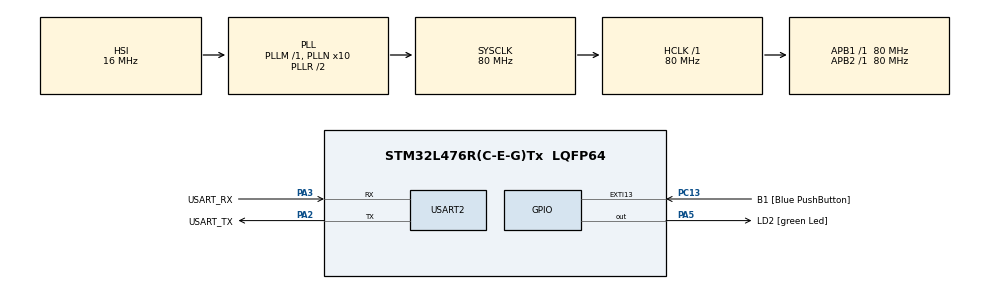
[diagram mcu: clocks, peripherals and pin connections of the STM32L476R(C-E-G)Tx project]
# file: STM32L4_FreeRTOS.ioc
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FREERTOS.Tasks01=defaultTask,0,128,StartDefaultTask,Default,NULL
Mcu.Family=STM32L4
Mcu.Name=STM32L476R(C-E-G)Tx
Mcu.Package=LQFP64
NVIC.PriorityGroup=NVIC_PRIORITYGROUP_4
NVIC.TIM6_DAC_IRQn=true\:0\:0\:false\:false\:true\:false\:false
NVIC.TimeBase=TIM6_DAC_IRQn
NVIC.TimeBaseIP=TIM6
PA13\ (JTMS-SWDIO).GPIO_Label=TMS
PA13\ (JTMS-SWDIO).Mode=Serial_Wire
PA13\ (JTMS-SWDIO).Signal=SYS_JTMS-SWDIO
PA14\ (JTCK-SWCLK).GPIO_Label=TCK
PA14\ (JTCK-SWCLK).Mode=Serial_Wire
PA14\ (JTCK-SWCLK).Signal=SYS_JTCK-SWCLK
PA2.GPIO_Label=USART_TX
PA2.GPIO_Mode=GPIO_MODE_AF_PP
PA2.GPIO_PuPd=GPIO_NOPULL
PA2.GPIO_Speed=GPIO_SPEED_FREQ_VERY_HIGH
PA2.Mode=Asynchronous
PA2.Signal=USART2_TX
PA3.GPIO_Label=USART_RX
PA3.GPIO_Mode=GPIO_MODE_AF_PP
PA3.GPIO_PuPd=GPIO_NOPULL
PA3.GPIO_Speed=GPIO_SPEED_FREQ_VERY_HIGH
PA3.Mode=Asynchronous
PA3.Signal=USART2_RX
PA5.GPIO_Label=LD2 [green Led]
PA5.GPIO_ModeDefaultOutputPP=GPIO_MODE_OUTPUT_PP
PA5.GPIO_PuPd=GPIO_NOPULL
PA5.GPIO_Speed=GPIO_SPEED_FREQ_LOW
PA5.Signal=GPIO_Output
PB3\ (JTDO-TRACESWO).GPIO_Label=SWO
PB3\ (JTDO-TRACESWO).Signal=SYS_JTDO-SWO
PC13.GPIO_Label=B1 [Blue PushButton]
PC13.GPIO_ModeDefaultEXTI=GPIO_MODE_IT_FALLING
PC13.GPIO_PuPd=GPIO_NOPULL
PC13.Signal=GPXTI13
PC14-OSC32_IN\ (PC14).Mode=LSE-External-Oscillator
PC14-OSC32_IN\ (PC14).Signal=RCC_OSC32_IN
PC15-OSC32_OUT\ (PC15).Mode=LSE-External-Oscillator
PC15-OSC32_OUT\ (PC15).Signal=RCC_OSC32_OUT
PH0-OSC_IN\ (PH0).Signal=RCC_OSC_IN
PH1-OSC_OUT\ (PH1).Signal=RCC_OSC_OUT
ProjectManager.HeapSize=0x200
ProjectManager.StackSize=0x400
ProjectManager.TargetToolchain=TrueSTUDIO
RCC.ADCFreq_Value=64000000
RCC.AHBFreq_Value=80000000
RCC.APB1Freq_Value=80000000
RCC.APB1TimFreq_Value=80000000
RCC.APB2Freq_Value=80000000
RCC.APB2TimFreq_Value=80000000
RCC.CortexFreq_Value=80000000
RCC.HCLKFreq_Value=80000000
RCC.HSE_VALUE=8000000
RCC.HSI_VALUE=16000000
RCC.MSI_VALUE=4000000
RCC.PLLN=10
RCC.PLLSourceVirtual=RCC_PLLSOURCE_HSI
RCC.PREFETCH_ENABLE=1
RCC.SYSCLKFreq_VALUE=80000000
RCC.SYSCLKSource=RCC_SYSCLKSOURCE_PLLCLK
RCC.USBFreq_Value=64000000
RCC.VCOOutputFreq_Value=160000000
USART2.VirtualMode-Asynchronous=VM_ASYNC
VP_FREERTOS_VS_ENABLE.Mode=Enabled
VP_SYS_VS_tim6.Mode=TIM6
board=NUCLEO-L476RG

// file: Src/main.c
/**
  ******************************************************************************
  * @file           : main.c
  * @brief          : Main program body
  ******************************************************************************
  * This notice applies to any and all portions of this file
  * that are not between comment pairs USER CODE BEGIN and
  * USER CODE END. Other portions of this file, whether
  * inserted by the user or by software development tools
  * are owned by their respective copyright owners.
  *
  * Copyright (c) 2018 STMicroelectronics International N.V.
  * All rights reserved.
  *
  * Redistribution and use in source and binary forms, with or without
  * modification, are permitted, provided that the following conditions are met:
  *
  * 1. Redistribution of source code must retain the above copyright notice,
  *    this list of conditions and the following disclaimer.
  * 2. Redistributions in binary form must reproduce the above copyright notice,
  *    this list of conditions and the following disclaimer in the documentation
  *    and/or other materials provided with the distribution.
  * 3. Neither the name of STMicroelectronics nor the names of other
  *    contributors to this software may be used to endorse or promote products
  *    derived from this software without specific written permission.
  * 4. This software, including modifications and/or derivative works of this
  *    software, must execute solely and exclusively on microcontroller or
  *    microprocessor devices manufactured by or for STMicroelectronics.
  * 5. Redistribution and use of this software other than as permitted under
  *    this license is void and will automatically terminate your rights under
  *    this license.
  *
  * THIS SOFTWARE IS PROVIDED BY STMICROELECTRONICS AND CONTRIBUTORS "AS IS"
  * AND ANY EXPRESS, IMPLIED OR STATUTORY WARRANTIES, INCLUDING, BUT NOT
  * LIMITED TO, THE IMPLIED WARRANTIES OF MERCHANTABILITY, FITNESS FOR A
  * PARTICULAR PURPOSE AND NON-INFRINGEMENT OF THIRD PARTY INTELLECTUAL PROPERTY
  * RIGHTS ARE DISCLAIMED TO THE FULLEST EXTENT PERMITTED BY LAW. IN NO EVENT
  * SHALL STMICROELECTRONICS OR CONTRIBUTORS BE LIABLE FOR ANY DIRECT, INDIRECT,
  * INCIDENTAL, SPECIAL, EXEMPLARY, OR CONSEQUENTIAL DAMAGES (INCLUDING, BUT NOT
  * LIMITED TO, PROCUREMENT OF SUBSTITUTE GOODS OR SERVICES; LOSS OF USE, DATA,
  * OR PROFITS; OR BUSINESS INTERRUPTION) HOWEVER CAUSED AND ON ANY THEORY OF
  * LIABILITY, WHETHER IN CONTRACT, STRICT LIABILITY, OR TORT (INCLUDING
  * NEGLIGENCE OR OTHERWISE) ARISING IN ANY WAY OUT OF THE USE OF THIS SOFTWARE,
  * EVEN IF ADVISED OF THE POSSIBILITY OF SUCH DAMAGE.
  *
  ******************************************************************************
  */
#include "main.h"
#include "stm32l4xx_hal.h"
#include "cmsis_os.h"

UART_HandleTypeDef huart2;

osThreadId defaultTaskHandle;

/* USER CODE BEGIN PV */
/* Private variables ---------------------------------------------------------*/

/* USER CODE END PV */

void SystemClock_Config(void);
static void MX_GPIO_Init(void);
static void MX_USART2_UART_Init(void);
void StartDefaultTask(void const * argument);

/* USER CODE BEGIN PFP */
/* Private function prototypes -----------------------------------------------*/

/* USER CODE END PFP */

/* USER CODE BEGIN 0 */

QueueHandle_t xQueue;

void vLedToggle(void *pvParameters)
{
	TickType_t xDelay = 1000 / portTICK_PERIOD_MS;

	while(1)
	{
		HAL_GPIO_TogglePin(GPIOA, GPIO_PIN_5);
		vTaskDelay(xDelay);
	}
}

void vUartTransmit(void *pvParameters)
{

	uint8_t txBuffer[7];

	uint8_t *ptr_txBuffer;

	ptr_txBuffer = txBuffer;

	uint8_t debugMsg[] = "vUartTransmit task initialized.\n";

	HAL_UART_Transmit(&huart2, debugMsg, sizeof(debugMsg), HAL_MAX_DELAY);

	while(1)
	{

		xQueueReceive(xQueue, &ptr_txBuffer, HAL_MAX_DELAY); // blocks until vUartReceive task adds data to queue

		HAL_UART_Transmit(&huart2, ptr_txBuffer, 7, HAL_MAX_DELAY); // once data is read from the queue, send it over to UART

	}
}

void vUartReceive(void *pvParameters)
{
	TickType_t xDelay = 100 / portTICK_PERIOD_MS;

	uint8_t rxBuffer[7]; // array is needed for HAL_UART_Receive()

	uint8_t *ptr_rxBuffer; // pointer to the array for xQueueSend

	ptr_rxBuffer = rxBuffer;

	uint8_t debugMsg[] = "vuartReceive task initialized.\n";

	HAL_UART_Transmit(&huart2, debugMsg, sizeof(debugMsg), HAL_MAX_DELAY);

	while(1)
	{

		HAL_UART_Receive(&huart2, rxBuffer, 7, HAL_MAX_DELAY); // poll on UART RX

		xQueueSend(xQueue, &ptr_rxBuffer, 0); // when 7 characters have been received, send the array to the queue

		vTaskDelay(xDelay); // block for 100ms
	}
}

/* USER CODE END 0 */

int main(void)

{

  /* MCU Configuration----------------------------------------------------------*/

  /* Reset of all peripherals, Initializes the Flash interface and the Systick. */
  HAL_Init();

  /* Configure the system clock */
  SystemClock_Config();

  /* Initialize all configured peripherals */
  MX_GPIO_Init();
  MX_USART2_UART_Init();

  /* USER CODE BEGIN 2 */

  xQueue = xQueueCreate(4, sizeof(int32_t));

  xTaskCreate(vLedToggle,
		  	 (const char* const)"LED Toggle",
			 configMINIMAL_STACK_SIZE,
			 0,
			 1,
			 NULL);

  xTaskCreate(vUartTransmit,
  		  	 (const char* const)"UART Transmit",
  			 configMINIMAL_STACK_SIZE,
  			 0,
  			 2,
			 NULL);

  xTaskCreate(vUartReceive,
  		  	 (const char* const)"UART Receive",
  			 configMINIMAL_STACK_SIZE,
  			 0,
  			 1,
			 NULL);

  /* Start FreeRTOS task scheduler. */
 vTaskStartScheduler();

  /* USER CODE END 2 */

  /* Create the thread(s) */
  /* definition and creation of defaultTask */
  osThreadDef(defaultTask, StartDefaultTask, osPriorityNormal, 0, 128);
  defaultTaskHandle = osThreadCreate(osThread(defaultTask), NULL);

  /* Start scheduler */
  osKernelStart();

  /* We should never get here as control is now taken by the scheduler */

  /* Infinite loop */
  while (1)
  {

  }

}

void SystemClock_Config(void)
{

  RCC_OscInitTypeDef RCC_OscInitStruct;
  RCC_ClkInitTypeDef RCC_ClkInitStruct;
  RCC_PeriphCLKInitTypeDef PeriphClkInit;

    /**Initializes the CPU, AHB and APB busses clocks
    */
  RCC_OscInitStruct.OscillatorType = RCC_OSCILLATORTYPE_HSI;
  RCC_OscInitStruct.HSIState = RCC_HSI_ON;
  RCC_OscInitStruct.HSICalibrationValue = 16;
  RCC_OscInitStruct.PLL.PLLState = RCC_PLL_ON;
  RCC_OscInitStruct.PLL.PLLSource = RCC_PLLSOURCE_HSI;
  RCC_OscInitStruct.PLL.PLLM = 1;
  RCC_OscInitStruct.PLL.PLLN = 10;
  RCC_OscInitStruct.PLL.PLLP = RCC_PLLP_DIV7;
  RCC_OscInitStruct.PLL.PLLQ = RCC_PLLQ_DIV2;
  RCC_OscInitStruct.PLL.PLLR = RCC_PLLR_DIV2;
  if (HAL_RCC_OscConfig(&RCC_OscInitStruct) != HAL_OK)
  {
    _Error_Handler(__FILE__, __LINE__);
  }

    /**Initializes the CPU, AHB and APB busses clocks
    */
  RCC_ClkInitStruct.ClockType = RCC_CLOCKTYPE_HCLK|RCC_CLOCKTYPE_SYSCLK
                              |RCC_CLOCKTYPE_PCLK1|RCC_CLOCKTYPE_PCLK2;
  RCC_ClkInitStruct.SYSCLKSource = RCC_SYSCLKSOURCE_PLLCLK;
  RCC_ClkInitStruct.AHBCLKDivider = RCC_SYSCLK_DIV1;
  RCC_ClkInitStruct.APB1CLKDivider = RCC_HCLK_DIV1;
  RCC_ClkInitStruct.APB2CLKDivider = RCC_HCLK_DIV1;

  if (HAL_RCC_ClockConfig(&RCC_ClkInitStruct, FLASH_LATENCY_4) != HAL_OK)
  {
    _Error_Handler(__FILE__, __LINE__);
  }

  PeriphClkInit.PeriphClockSelection = RCC_PERIPHCLK_USART2;
  PeriphClkInit.Usart2ClockSelection = RCC_USART2CLKSOURCE_PCLK1;
  if (HAL_RCCEx_PeriphCLKConfig(&PeriphClkInit) != HAL_OK)
  {
    _Error_Handler(__FILE__, __LINE__);
  }

    /**Configure the main internal regulator output voltage
    */
  if (HAL_PWREx_ControlVoltageScaling(PWR_REGULATOR_VOLTAGE_SCALE1) != HAL_OK)
  {
    _Error_Handler(__FILE__, __LINE__);
  }

    /**Configure the Systick interrupt time
    */
  HAL_SYSTICK_Config(HAL_RCC_GetHCLKFreq()/1000);

    /**Configure the Systick
    */
  HAL_SYSTICK_CLKSourceConfig(SYSTICK_CLKSOURCE_HCLK);

  /* SysTick_IRQn interrupt configuration */
  HAL_NVIC_SetPriority(SysTick_IRQn, 15, 0);
}

/* USART2 init function */
static void MX_USART2_UART_Init(void)
{

  huart2.Instance = USART2;
  huart2.Init.BaudRate = 115200;
  huart2.Init.WordLength = UART_WORDLENGTH_8B;
  huart2.Init.StopBits = UART_STOPBITS_1;
  huart2.Init.Parity = UART_PARITY_NONE;
  huart2.Init.Mode = UART_MODE_TX_RX;
  huart2.Init.HwFlowCtl = UART_HWCONTROL_NONE;
  huart2.Init.OverSampling = UART_OVERSAMPLING_16;
  huart2.Init.OneBitSampling = UART_ONE_BIT_SAMPLE_DISABLE;
  huart2.AdvancedInit.AdvFeatureInit = UART_ADVFEATURE_NO_INIT;
  if (HAL_UART_Init(&huart2) != HAL_OK)
  {
    _Error_Handler(__FILE__, __LINE__);
  }

}

/** Configure pins as
        * Analog
        * Input
        * Output
        * EVENT_OUT
        * EXTI
        * Free pins are configured automatically as Analog (this feature is enabled through
        * the Code Generation settings)
*/
static void MX_GPIO_Init(void)
{

  GPIO_InitTypeDef GPIO_InitStruct;

  /* GPIO Ports Clock Enable */
  __HAL_RCC_GPIOC_CLK_ENABLE();
  __HAL_RCC_GPIOH_CLK_ENABLE();
  __HAL_RCC_GPIOA_CLK_ENABLE();
  __HAL_RCC_GPIOB_CLK_ENABLE();
  __HAL_RCC_GPIOD_CLK_ENABLE();

  /*Configure GPIO pin Output Level */
  HAL_GPIO_WritePin(GPIOA, LD2_Pin|GPIO_PIN_8|GPIO_PIN_9|GPIO_PIN_10, GPIO_PIN_RESET);

  /*Configure GPIO pin Output Level */
  HAL_GPIO_WritePin(GPIOB, GPIO_PIN_10, GPIO_PIN_RESET);

  /*Configure GPIO pin : B1_Pin */
  GPIO_InitStruct.Pin = B1_Pin;
  GPIO_InitStruct.Mode = GPIO_MODE_IT_FALLING;
  GPIO_InitStruct.Pull = GPIO_NOPULL;
  HAL_GPIO_Init(B1_GPIO_Port, &GPIO_InitStruct);

  /*Configure GPIO pins : PC0 PC1 PC2 PC3
                           PC4 PC5 PC6 PC7
                           PC8 PC9 PC10 PC11
                           PC12 */
  GPIO_InitStruct.Pin = GPIO_PIN_0|GPIO_PIN_1|GPIO_PIN_2|GPIO_PIN_3
                          |GPIO_PIN_4|GPIO_PIN_5|GPIO_PIN_6|GPIO_PIN_7
                          |GPIO_PIN_8|GPIO_PIN_9|GPIO_PIN_10|GPIO_PIN_11
                          |GPIO_PIN_12;
  GPIO_InitStruct.Mode = GPIO_MODE_ANALOG;
  GPIO_InitStruct.Pull = GPIO_NOPULL;
  HAL_GPIO_Init(GPIOC, &GPIO_InitStruct);

  /*Configure GPIO pins : PA0 PA1 PA4 PA6
                           PA7 PA11 PA12 PA15 */
  GPIO_InitStruct.Pin = GPIO_PIN_0|GPIO_PIN_1|GPIO_PIN_4|GPIO_PIN_6
                          |GPIO_PIN_7|GPIO_PIN_11|GPIO_PIN_12|GPIO_PIN_15;
  GPIO_InitStruct.Mode = GPIO_MODE_ANALOG;
  GPIO_InitStruct.Pull = GPIO_NOPULL;
  HAL_GPIO_Init(GPIOA, &GPIO_InitStruct);

  /*Configure GPIO pins : LD2_Pin PA8 PA9 PA10 */
  GPIO_InitStruct.Pin = LD2_Pin|GPIO_PIN_8|GPIO_PIN_9|GPIO_PIN_10;
  GPIO_InitStruct.Mode = GPIO_MODE_OUTPUT_PP;
  GPIO_InitStruct.Pull = GPIO_NOPULL;
  GPIO_InitStruct.Speed = GPIO_SPEED_FREQ_LOW;
  HAL_GPIO_Init(GPIOA, &GPIO_InitStruct);

  /*Configure GPIO pins : PB0 PB1 PB2 PB11
                           PB12 PB13 PB14 PB15
                           PB4 PB5 PB6 PB7
                           PB8 PB9 */
  GPIO_InitStruct.Pin = GPIO_PIN_0|GPIO_PIN_1|GPIO_PIN_2|GPIO_PIN_11
                          |GPIO_PIN_12|GPIO_PIN_13|GPIO_PIN_14|GPIO_PIN_15
                          |GPIO_PIN_4|GPIO_PIN_5|GPIO_PIN_6|GPIO_PIN_7
                          |GPIO_PIN_8|GPIO_PIN_9;
  GPIO_InitStruct.Mode = GPIO_MODE_ANALOG;
  GPIO_InitStruct.Pull = GPIO_NOPULL;
  HAL_GPIO_Init(GPIOB, &GPIO_InitStruct);

  /*Configure GPIO pin : PB10 */
  GPIO_InitStruct.Pin = GPIO_PIN_10;
  GPIO_InitStruct.Mode = GPIO_MODE_OUTPUT_PP;
  GPIO_InitStruct.Pull = GPIO_NOPULL;
  GPIO_InitStruct.Speed = GPIO_SPEED_FREQ_LOW;
  HAL_GPIO_Init(GPIOB, &GPIO_InitStruct);

  /*Configure GPIO pin : PD2 */
  GPIO_InitStruct.Pin = GPIO_PIN_2;
  GPIO_InitStruct.Mode = GPIO_MODE_ANALOG;
  GPIO_InitStruct.Pull = GPIO_NOPULL;
  HAL_GPIO_Init(GPIOD, &GPIO_InitStruct);

}

/* StartDefaultTask function */
void StartDefaultTask(void const * argument)
{

  for(;;)
  {
    osDelay(1);
  }
}

void HAL_TIM_PeriodElapsedCallback(TIM_HandleTypeDef *htim)
{
  if (htim->Instance == TIM6) {
    HAL_IncTick();
  }
}

void _Error_Handler(char *file, int line)
{
  while(1)
  {
  }
}

/************************ (C) COPYRIGHT STMicroelectronics *****END OF FILE****/
